VERSION 5.7 ;
BUSBITCHARS "[]" ;
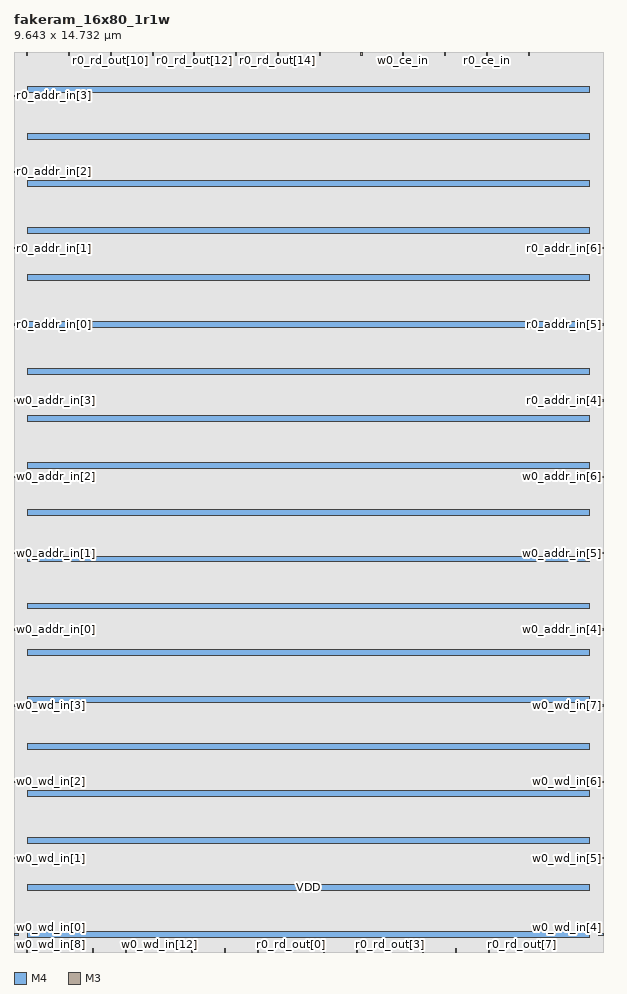
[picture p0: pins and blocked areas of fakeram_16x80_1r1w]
MACRO fakeram_16x80_1r1w
  FOREIGN fakeram_16x80_1r1w 0 0 ;
  SYMMETRY X Y R90 ;
  SIZE 9.643 BY 14.732 ;
  CLASS BLOCK ;
  PIN w0_wd_in[0]
    DIRECTION INPUT ;
    USE SIGNAL ;
    SHAPE ABUTMENT ;
    PORT
      LAYER M4 ;
      RECT 0.000 0.276 0.072 0.300 ;
    END
  END w0_wd_in[0]
  PIN w0_wd_in[1]
    DIRECTION INPUT ;
    USE SIGNAL ;
    SHAPE ABUTMENT ;
    PORT
      LAYER M4 ;
      RECT 0.000 1.524 0.072 1.548 ;
    END
  END w0_wd_in[1]
  PIN w0_wd_in[2]
    DIRECTION INPUT ;
    USE SIGNAL ;
    SHAPE ABUTMENT ;
    PORT
      LAYER M4 ;
      RECT 0.000 2.772 0.072 2.796 ;
    END
  END w0_wd_in[2]
  PIN w0_wd_in[3]
    DIRECTION INPUT ;
    USE SIGNAL ;
    SHAPE ABUTMENT ;
    PORT
      LAYER M4 ;
      RECT 0.000 4.020 0.072 4.044 ;
    END
  END w0_wd_in[3]
  PIN w0_wd_in[4]
    DIRECTION INPUT ;
    USE SIGNAL ;
    SHAPE ABUTMENT ;
    PORT
      LAYER M4 ;
      RECT 9.571 0.276 9.643 0.300 ;
    END
  END w0_wd_in[4]
  PIN w0_wd_in[5]
    DIRECTION INPUT ;
    USE SIGNAL ;
    SHAPE ABUTMENT ;
    PORT
      LAYER M4 ;
      RECT 9.571 1.524 9.643 1.548 ;
    END
  END w0_wd_in[5]
  PIN w0_wd_in[6]
    DIRECTION INPUT ;
    USE SIGNAL ;
    SHAPE ABUTMENT ;
    PORT
      LAYER M4 ;
      RECT 9.571 2.772 9.643 2.796 ;
    END
  END w0_wd_in[6]
  PIN w0_wd_in[7]
    DIRECTION INPUT ;
    USE SIGNAL ;
    SHAPE ABUTMENT ;
    PORT
      LAYER M4 ;
      RECT 9.571 4.020 9.643 4.044 ;
    END
  END w0_wd_in[7]
  PIN w0_wd_in[8]
    DIRECTION OUTPUT ;
    USE SIGNAL ;
    SHAPE ABUTMENT ;
    PORT
      LAYER M3 ;
      RECT 0.207 0.000 0.225 0.054 ;
    END
  END w0_wd_in[8]
  PIN w0_wd_in[9]
    DIRECTION OUTPUT ;
    USE SIGNAL ;
    SHAPE ABUTMENT ;
    PORT
      LAYER M3 ;
      RECT 0.747 0.000 0.765 0.054 ;
    END
  END w0_wd_in[9]
  PIN w0_wd_in[10]
    DIRECTION OUTPUT ;
    USE SIGNAL ;
    SHAPE ABUTMENT ;
    PORT
      LAYER M3 ;
      RECT 1.287 0.000 1.305 0.054 ;
    END
  END w0_wd_in[10]
  PIN w0_wd_in[11]
    DIRECTION OUTPUT ;
    USE SIGNAL ;
    SHAPE ABUTMENT ;
    PORT
      LAYER M3 ;
      RECT 1.827 0.000 1.845 0.054 ;
    END
  END w0_wd_in[11]
  PIN w0_wd_in[12]
    DIRECTION OUTPUT ;
    USE SIGNAL ;
    SHAPE ABUTMENT ;
    PORT
      LAYER M3 ;
      RECT 2.367 0.000 2.385 0.054 ;
    END
  END w0_wd_in[12]
  PIN w0_wd_in[13]
    DIRECTION OUTPUT ;
    USE SIGNAL ;
    SHAPE ABUTMENT ;
    PORT
      LAYER M3 ;
      RECT 2.907 0.000 2.925 0.054 ;
    END
  END w0_wd_in[13]
  PIN w0_wd_in[14]
    DIRECTION OUTPUT ;
    USE SIGNAL ;
    SHAPE ABUTMENT ;
    PORT
      LAYER M3 ;
      RECT 3.447 0.000 3.465 0.054 ;
    END
  END w0_wd_in[14]
  PIN w0_wd_in[15]
    DIRECTION OUTPUT ;
    USE SIGNAL ;
    SHAPE ABUTMENT ;
    PORT
      LAYER M3 ;
      RECT 3.987 0.000 4.005 0.054 ;
    END
  END w0_wd_in[15]
  PIN r0_rd_out[0]
    DIRECTION OUTPUT ;
    USE SIGNAL ;
    SHAPE ABUTMENT ;
    PORT
      LAYER M3 ;
      RECT 4.527 0.000 4.545 0.054 ;
    END
  END r0_rd_out[0]
  PIN r0_rd_out[1]
    DIRECTION OUTPUT ;
    USE SIGNAL ;
    SHAPE ABUTMENT ;
    PORT
      LAYER M3 ;
      RECT 5.067 0.000 5.085 0.054 ;
    END
  END r0_rd_out[1]
  PIN r0_rd_out[2]
    DIRECTION OUTPUT ;
    USE SIGNAL ;
    SHAPE ABUTMENT ;
    PORT
      LAYER M3 ;
      RECT 5.607 0.000 5.625 0.054 ;
    END
  END r0_rd_out[2]
  PIN r0_rd_out[3]
    DIRECTION OUTPUT ;
    USE SIGNAL ;
    SHAPE ABUTMENT ;
    PORT
      LAYER M3 ;
      RECT 6.147 0.000 6.165 0.054 ;
    END
  END r0_rd_out[3]
  PIN r0_rd_out[4]
    DIRECTION OUTPUT ;
    USE SIGNAL ;
    SHAPE ABUTMENT ;
    PORT
      LAYER M3 ;
      RECT 6.687 0.000 6.705 0.054 ;
    END
  END r0_rd_out[4]
  PIN r0_rd_out[5]
    DIRECTION OUTPUT ;
    USE SIGNAL ;
    SHAPE ABUTMENT ;
    PORT
      LAYER M3 ;
      RECT 7.227 0.000 7.245 0.054 ;
    END
  END r0_rd_out[5]
  PIN r0_rd_out[6]
    DIRECTION OUTPUT ;
    USE SIGNAL ;
    SHAPE ABUTMENT ;
    PORT
      LAYER M3 ;
      RECT 7.767 0.000 7.785 0.054 ;
    END
  END r0_rd_out[6]
  PIN r0_rd_out[7]
    DIRECTION OUTPUT ;
    USE SIGNAL ;
    SHAPE ABUTMENT ;
    PORT
      LAYER M3 ;
      RECT 8.307 0.000 8.325 0.054 ;
    END
  END r0_rd_out[7]
  PIN r0_rd_out[8]
    DIRECTION OUTPUT ;
    USE SIGNAL ;
    SHAPE ABUTMENT ;
    PORT
      LAYER M3 ;
      RECT 0.207 14.678 0.225 14.732 ;
    END
  END r0_rd_out[8]
  PIN r0_rd_out[9]
    DIRECTION OUTPUT ;
    USE SIGNAL ;
    SHAPE ABUTMENT ;
    PORT
      LAYER M3 ;
      RECT 0.891 14.678 0.909 14.732 ;
    END
  END r0_rd_out[9]
  PIN r0_rd_out[10]
    DIRECTION OUTPUT ;
    USE SIGNAL ;
    SHAPE ABUTMENT ;
    PORT
      LAYER M3 ;
      RECT 1.575 14.678 1.593 14.732 ;
    END
  END r0_rd_out[10]
  PIN r0_rd_out[11]
    DIRECTION OUTPUT ;
    USE SIGNAL ;
    SHAPE ABUTMENT ;
    PORT
      LAYER M3 ;
      RECT 2.259 14.678 2.277 14.732 ;
    END
  END r0_rd_out[11]
  PIN r0_rd_out[12]
    DIRECTION OUTPUT ;
    USE SIGNAL ;
    SHAPE ABUTMENT ;
    PORT
      LAYER M3 ;
      RECT 2.943 14.678 2.961 14.732 ;
    END
  END r0_rd_out[12]
  PIN r0_rd_out[13]
    DIRECTION OUTPUT ;
    USE SIGNAL ;
    SHAPE ABUTMENT ;
    PORT
      LAYER M3 ;
      RECT 3.627 14.678 3.645 14.732 ;
    END
  END r0_rd_out[13]
  PIN r0_rd_out[14]
    DIRECTION OUTPUT ;
    USE SIGNAL ;
    SHAPE ABUTMENT ;
    PORT
      LAYER M3 ;
      RECT 4.311 14.678 4.329 14.732 ;
    END
  END r0_rd_out[14]
  PIN r0_rd_out[15]
    DIRECTION OUTPUT ;
    USE SIGNAL ;
    SHAPE ABUTMENT ;
    PORT
      LAYER M3 ;
      RECT 4.995 14.678 5.013 14.732 ;
    END
  END r0_rd_out[15]
  PIN w0_addr_in[0]
    DIRECTION INPUT ;
    USE SIGNAL ;
    SHAPE ABUTMENT ;
    PORT
      LAYER M4 ;
      RECT 0.000 5.268 0.072 5.292 ;
    END
  END w0_addr_in[0]
  PIN w0_addr_in[1]
    DIRECTION INPUT ;
    USE SIGNAL ;
    SHAPE ABUTMENT ;
    PORT
      LAYER M4 ;
      RECT 0.000 6.516 0.072 6.540 ;
    END
  END w0_addr_in[1]
  PIN w0_addr_in[2]
    DIRECTION INPUT ;
    USE SIGNAL ;
    SHAPE ABUTMENT ;
    PORT
      LAYER M4 ;
      RECT 0.000 7.764 0.072 7.788 ;
    END
  END w0_addr_in[2]
  PIN w0_addr_in[3]
    DIRECTION INPUT ;
    USE SIGNAL ;
    SHAPE ABUTMENT ;
    PORT
      LAYER M4 ;
      RECT 0.000 9.012 0.072 9.036 ;
    END
  END w0_addr_in[3]
  PIN w0_addr_in[4]
    DIRECTION INPUT ;
    USE SIGNAL ;
    SHAPE ABUTMENT ;
    PORT
      LAYER M4 ;
      RECT 9.571 5.268 9.643 5.292 ;
    END
  END w0_addr_in[4]
  PIN w0_addr_in[5]
    DIRECTION INPUT ;
    USE SIGNAL ;
    SHAPE ABUTMENT ;
    PORT
      LAYER M4 ;
      RECT 9.571 6.516 9.643 6.540 ;
    END
  END w0_addr_in[5]
  PIN w0_addr_in[6]
    DIRECTION INPUT ;
    USE SIGNAL ;
    SHAPE ABUTMENT ;
    PORT
      LAYER M4 ;
      RECT 9.571 7.764 9.643 7.788 ;
    END
  END w0_addr_in[6]
  PIN r0_addr_in[0]
    DIRECTION INPUT ;
    USE SIGNAL ;
    SHAPE ABUTMENT ;
    PORT
      LAYER M4 ;
      RECT 0.000 10.260 0.072 10.284 ;
    END
  END r0_addr_in[0]
  PIN r0_addr_in[1]
    DIRECTION INPUT ;
    USE SIGNAL ;
    SHAPE ABUTMENT ;
    PORT
      LAYER M4 ;
      RECT 0.000 11.508 0.072 11.532 ;
    END
  END r0_addr_in[1]
  PIN r0_addr_in[2]
    DIRECTION INPUT ;
    USE SIGNAL ;
    SHAPE ABUTMENT ;
    PORT
      LAYER M4 ;
      RECT 0.000 12.756 0.072 12.780 ;
    END
  END r0_addr_in[2]
  PIN r0_addr_in[3]
    DIRECTION INPUT ;
    USE SIGNAL ;
    SHAPE ABUTMENT ;
    PORT
      LAYER M4 ;
      RECT 0.000 14.004 0.072 14.028 ;
    END
  END r0_addr_in[3]
  PIN r0_addr_in[4]
    DIRECTION INPUT ;
    USE SIGNAL ;
    SHAPE ABUTMENT ;
    PORT
      LAYER M4 ;
      RECT 9.571 9.012 9.643 9.036 ;
    END
  END r0_addr_in[4]
  PIN r0_addr_in[5]
    DIRECTION INPUT ;
    USE SIGNAL ;
    SHAPE ABUTMENT ;
    PORT
      LAYER M4 ;
      RECT 9.571 10.260 9.643 10.284 ;
    END
  END r0_addr_in[5]
  PIN r0_addr_in[6]
    DIRECTION INPUT ;
    USE SIGNAL ;
    SHAPE ABUTMENT ;
    PORT
      LAYER M4 ;
      RECT 9.571 11.508 9.643 11.532 ;
    END
  END r0_addr_in[6]
  PIN w0_we_in
    DIRECTION INPUT ;
    USE SIGNAL ;
    SHAPE ABUTMENT ;
    PORT
      LAYER M3 ;
      RECT 5.679 14.678 5.697 14.732 ;
    END
  END w0_we_in
  PIN w0_ce_in
    DIRECTION INPUT ;
    USE SIGNAL ;
    SHAPE ABUTMENT ;
    PORT
      LAYER M3 ;
      RECT 6.363 14.678 6.381 14.732 ;
    END
  END w0_ce_in
  PIN w0_clk
    DIRECTION INPUT ;
    USE SIGNAL ;
    SHAPE ABUTMENT ;
    PORT
      LAYER M3 ;
      RECT 7.047 14.678 7.065 14.732 ;
    END
  END w0_clk
  PIN r0_ce_in
    DIRECTION INPUT ;
    USE SIGNAL ;
    SHAPE ABUTMENT ;
    PORT
      LAYER M3 ;
      RECT 7.731 14.678 7.749 14.732 ;
    END
  END r0_ce_in
  PIN r0_clk
    DIRECTION INPUT ;
    USE SIGNAL ;
    SHAPE ABUTMENT ;
    PORT
      LAYER M3 ;
      RECT 8.415 14.678 8.433 14.732 ;
    END
  END r0_clk
  PIN VSS
    DIRECTION INOUT ;
    USE GROUND ;
    PORT
      LAYER M4 ;
      RECT 0.216 0.240 9.427 0.336 ;
      RECT 0.216 1.008 9.427 1.104 ;
      RECT 0.216 1.776 9.427 1.872 ;
      RECT 0.216 2.544 9.427 2.640 ;
      RECT 0.216 3.312 9.427 3.408 ;
      RECT 0.216 4.080 9.427 4.176 ;
      RECT 0.216 4.848 9.427 4.944 ;
      RECT 0.216 5.616 9.427 5.712 ;
      RECT 0.216 6.384 9.427 6.480 ;
      RECT 0.216 7.152 9.427 7.248 ;
      RECT 0.216 7.920 9.427 8.016 ;
      RECT 0.216 8.688 9.427 8.784 ;
      RECT 0.216 9.456 9.427 9.552 ;
      RECT 0.216 10.224 9.427 10.320 ;
      RECT 0.216 10.992 9.427 11.088 ;
      RECT 0.216 11.760 9.427 11.856 ;
      RECT 0.216 12.528 9.427 12.624 ;
      RECT 0.216 13.296 9.427 13.392 ;
      RECT 0.216 14.064 9.427 14.160 ;
    END
  END VSS
  PIN VDD
    DIRECTION INOUT ;
    USE POWER ;
    PORT
      LAYER M4 ;
      RECT 0.216 0.240 9.427 0.336 ;
      RECT 0.216 1.008 9.427 1.104 ;
      RECT 0.216 1.776 9.427 1.872 ;
      RECT 0.216 2.544 9.427 2.640 ;
      RECT 0.216 3.312 9.427 3.408 ;
      RECT 0.216 4.080 9.427 4.176 ;
      RECT 0.216 4.848 9.427 4.944 ;
      RECT 0.216 5.616 9.427 5.712 ;
      RECT 0.216 6.384 9.427 6.480 ;
      RECT 0.216 7.152 9.427 7.248 ;
      RECT 0.216 7.920 9.427 8.016 ;
      RECT 0.216 8.688 9.427 8.784 ;
      RECT 0.216 9.456 9.427 9.552 ;
      RECT 0.216 10.224 9.427 10.320 ;
      RECT 0.216 10.992 9.427 11.088 ;
      RECT 0.216 11.760 9.427 11.856 ;
      RECT 0.216 12.528 9.427 12.624 ;
      RECT 0.216 13.296 9.427 13.392 ;
      RECT 0.216 14.064 9.427 14.160 ;
    END
  END VDD
  OBS
    LAYER M1 ;
    RECT 0 0 9.643 14.732 ;
    LAYER M2 ;
    RECT 0 0 9.643 14.732 ;
    LAYER M3 ;
    RECT 0 0 9.643 14.732 ;
    LAYER M4 ;
    RECT 0 0 9.643 14.732 ;
  END
END fakeram_16x80_1r1w

END LIBRARY
